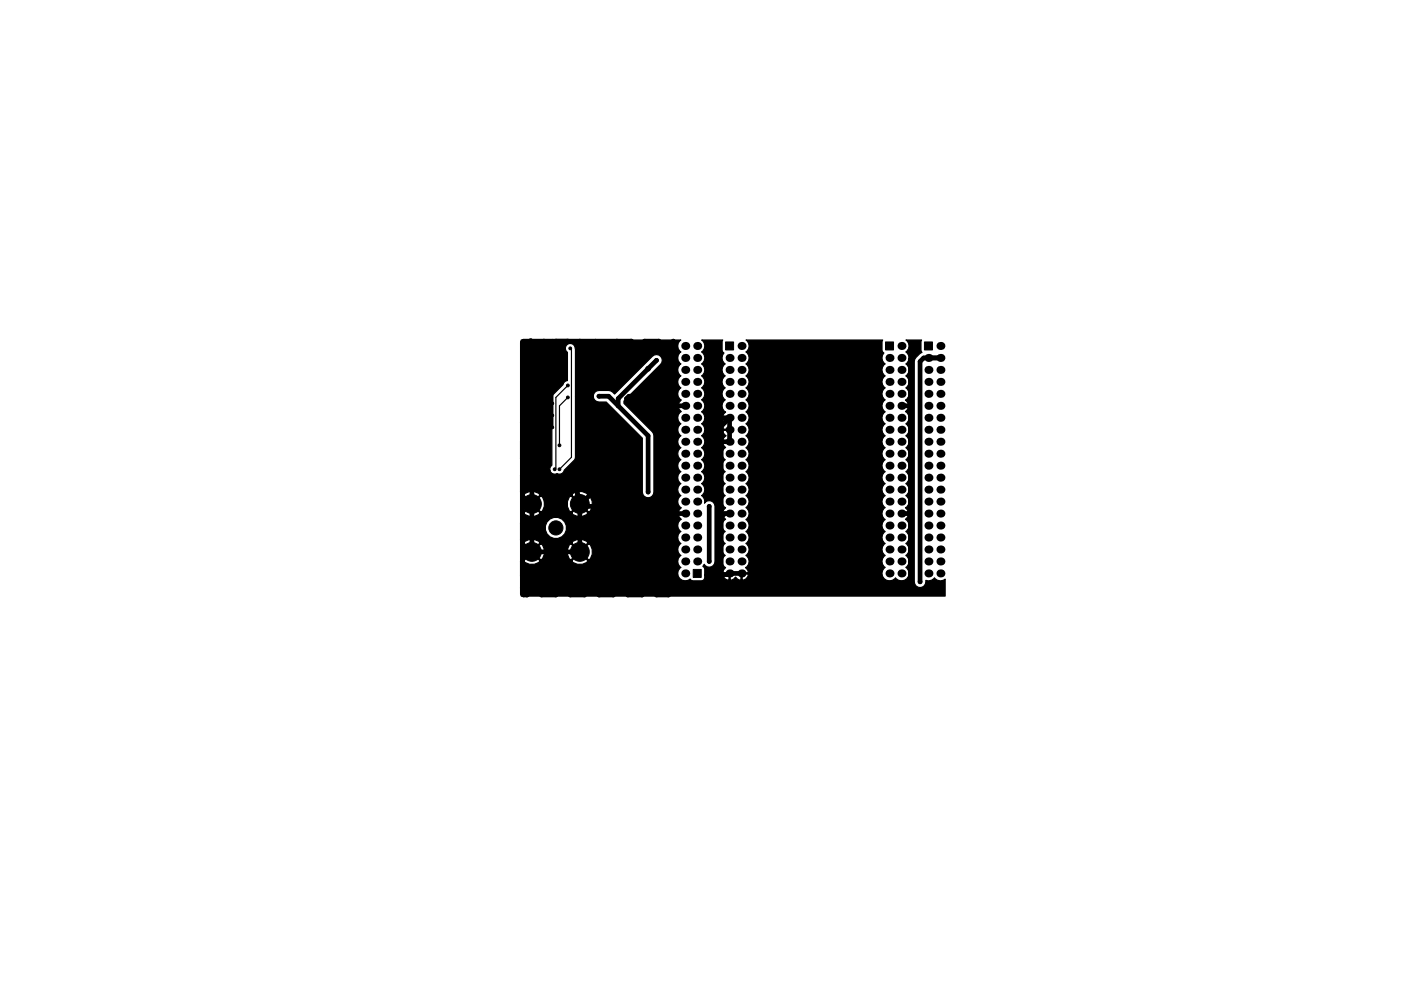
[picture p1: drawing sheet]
<svg xmlns="http://www.w3.org/2000/svg" width="297mm" height="210mm" viewBox="0 0 297 210" stroke-linecap="round" stroke-linejoin="round" font-family="sans-serif">
<g fill="#000" stroke="#000" stroke-width=".21">
<path d="M153.8 72.6h1.7v1.7h-1.7zM187.7 72.6h1.7v1.7h-1.7zM196 72.6h1.7v1.7h-1.7zM147 120.8h1.7v1.7h-1.7z"/>
<circle cx="112.5" cy="72.4" r=".5"/>
<circle cx="115.3" cy="72.4" r=".4"/>
<circle cx="117.1" cy="78" r=".3"/>
<circle cx="117.1" cy="75.4" r=".3"/>
<circle cx="117.9" cy="72.4" r=".4"/>
<circle cx="120.4" cy="72.4" r=".4"/>
<circle cx="120.9" cy="73.9" r=".3"/>
<circle cx="122.9" cy="72.4" r=".4"/>
<circle cx="126.2" cy="75.4" r=".3"/>
<circle cx="126.2" cy="77.5" r=".3"/>
<circle cx="130.8" cy="72.4" r=".4"/>
<circle cx="133.9" cy="74.9" r=".5"/>
<circle cx="133.9" cy="72.4" r=".4"/>
<circle cx="136.7" cy="72.4" r=".4"/>
<circle cx="137.4" cy="78.2" r=".5"/>
<circle cx="139.2" cy="76.4" r=".4"/>
<circle cx="139.7" cy="72.4" r=".4"/>
<circle cx="142.7" cy="72.4" r=".4"/>
<circle cx="193" cy="76.2" r=".4"/>
<circle cx="110.7" cy="93.7" r=".4"/>
<circle cx="110.7" cy="89.7" r=".4"/>
<circle cx="110.7" cy="97.3" r=".4"/>
<circle cx="117.1" cy="88.1" r=".3"/>
<circle cx="117.1" cy="85.6" r=".3"/>
<circle cx="117.1" cy="83.1" r=".3"/>
<circle cx="117.1" cy="90.7" r=".3"/>
<circle cx="117.1" cy="80.5" r=".3"/>
<circle cx="117.6" cy="99.6" r=".3"/>
<circle cx="118.6" cy="99.6" r=".3"/>
<circle cx="118.6" cy="94.5" r=".3"/>
<circle cx="120.4" cy="84.3" r=".3"/>
<circle cx="120.4" cy="81.8" r=".3"/>
<circle cx="122.4" cy="92.5" r=".4"/>
<circle cx="125.5" cy="91.9" r=".4"/>
<circle cx="126.2" cy="82" r=".3"/>
<circle cx="127" cy="84.1" r=".4"/>
<circle cx="127.3" cy="98.8" r=".5"/>
<circle cx="127.5" cy="91.9" r=".4"/>
<circle cx="131.6" cy="91.9" r=".4"/>
<circle cx="132.8" cy="84.6" r=".4"/>
<circle cx="135.4" cy="84.1" r=".5"/>
<circle cx="143.3" cy="93.2" r=".4"/>
<circle cx="143.3" cy="89.1" r=".4"/>
<circle cx="143.3" cy="86.1" r=".4"/>
<circle cx="143.3" cy="97.3" r=".4"/>
<circle cx="143.3" cy="83.6" r=".4"/>
<circle cx="143.3" cy="95.2" r=".4"/>
<circle cx="143.3" cy="91.2" r=".4"/>
<circle cx="143.3" cy="99.3" r=".4"/>
<circle cx="151.4" cy="82" r=".4"/>
<circle cx="110.7" cy="119.1" r=".4"/>
<circle cx="110.7" cy="114.5" r=".4"/>
<circle cx="110.7" cy="100.8" r=".4"/>
<circle cx="110.7" cy="111" r=".4"/>
<circle cx="110.7" cy="104.4" r=".4"/>
<circle cx="112.8" cy="106.9" r="2"/>
<circle cx="112.8" cy="117.1" r="2"/>
<circle cx="117.9" cy="112" r="1.5"/>
<circle cx="122.9" cy="117.1" r="2"/>
<circle cx="122.9" cy="106.9" r="2"/>
<circle cx="127.3" cy="102.9" r=".5"/>
<circle cx="134.9" cy="107.4" r=".4"/>
<circle cx="137.4" cy="104.4" r=".4"/>
<circle cx="143.3" cy="111.5" r=".4"/>
<circle cx="143.3" cy="101.3" r=".4"/>
<circle cx="143.3" cy="109.5" r=".4"/>
<circle cx="143.3" cy="105.4" r=".4"/>
<circle cx="143.3" cy="118.1" r=".4"/>
<circle cx="143.3" cy="103.4" r=".4"/>
<circle cx="143.3" cy="107.4" r=".4"/>
<circle cx="143.3" cy="116.1" r=".4"/>
<circle cx="143.3" cy="113.5" r=".4"/>
<circle cx="150.4" cy="107.4" r=".4"/>
<circle cx="150.4" cy="119.1" r=".4"/>
<circle cx="193" cy="119.4" r=".4"/>
<circle cx="193" cy="116.1" r=".4"/>
<circle cx="110.7" cy="122.2" r=".4"/>
<circle cx="110.7" cy="124.7" r=".4"/>
<circle cx="111.8" cy="126.2" r=".4"/>
<circle cx="114.8" cy="126.2" r=".4"/>
<circle cx="117.9" cy="126.2" r=".4"/>
<circle cx="120.9" cy="126.2" r=".4"/>
<circle cx="124" cy="126.2" r=".4"/>
<circle cx="127" cy="126.2" r=".4"/>
<circle cx="130" cy="126.2" r=".4"/>
<circle cx="133.1" cy="126.2" r=".4"/>
<circle cx="136.1" cy="126.2" r=".4"/>
<circle cx="139.2" cy="126.2" r=".4"/>
<circle cx="141.7" cy="126.2" r=".4"/>
<circle cx="143.3" cy="122.2" r=".4"/>
<circle cx="143.3" cy="125.2" r=".4"/>
<circle cx="143.3" cy="120.1" r=".4"/>
<circle cx="195.1" cy="123.4" r=".4"/>
</g>
<g fill="#000">
<circle cx="145.3" cy="78.5" r=".85"/>
<circle cx="145.3" cy="75.9" r=".85"/>
<circle cx="145.3" cy="73.4" r=".85"/>
<circle cx="147.8" cy="78.5" r=".85"/>
<circle cx="147.8" cy="73.4" r=".85"/>
<circle cx="147.8" cy="75.9" r=".85"/>
<circle cx="154.7" cy="78.5" r=".85"/>
<circle cx="154.7" cy="75.9" r=".85"/>
<circle cx="157.2" cy="78.5" r=".85"/>
<circle cx="157.2" cy="73.4" r=".85"/>
<circle cx="157.2" cy="75.9" r=".85"/>
<circle cx="188.6" cy="78.5" r=".85"/>
<circle cx="188.6" cy="75.9" r=".85"/>
<circle cx="191.1" cy="78.5" r=".85"/>
<circle cx="191.1" cy="73.4" r=".85"/>
<circle cx="191.1" cy="75.9" r=".85"/>
<circle cx="196.8" cy="78.5" r=".85"/>
<circle cx="196.8" cy="75.9" r=".85"/>
<circle cx="199.4" cy="73.4" r=".85"/>
<circle cx="199.4" cy="78.5" r=".85"/>
<circle cx="199.4" cy="75.9" r=".85"/>
<circle cx="145.3" cy="96.3" r=".85"/>
<circle cx="145.3" cy="88.6" r=".85"/>
<circle cx="145.3" cy="83.6" r=".85"/>
<circle cx="145.3" cy="81" r=".85"/>
<circle cx="145.3" cy="93.7" r=".85"/>
<circle cx="145.3" cy="86.1" r=".85"/>
<circle cx="145.3" cy="98.8" r=".85"/>
<circle cx="145.3" cy="91.2" r=".85"/>
<circle cx="147.8" cy="93.7" r=".85"/>
<circle cx="147.8" cy="88.6" r=".85"/>
<circle cx="147.8" cy="86.1" r=".85"/>
<circle cx="147.8" cy="96.3" r=".85"/>
<circle cx="147.8" cy="91.2" r=".85"/>
<circle cx="147.8" cy="81" r=".85"/>
<circle cx="147.8" cy="98.8" r=".85"/>
<circle cx="147.8" cy="83.6" r=".85"/>
<circle cx="154.7" cy="93.7" r=".85"/>
<circle cx="154.7" cy="96.3" r=".85"/>
<circle cx="154.7" cy="81" r=".85"/>
<circle cx="154.7" cy="86.1" r=".85"/>
<circle cx="154.7" cy="83.6" r=".85"/>
<circle cx="154.7" cy="91.2" r=".85"/>
<circle cx="154.7" cy="98.8" r=".85"/>
<circle cx="154.7" cy="88.6" r=".85"/>
<circle cx="157.2" cy="96.3" r=".85"/>
<circle cx="157.2" cy="93.7" r=".85"/>
<circle cx="157.2" cy="86.1" r=".85"/>
<circle cx="157.2" cy="81" r=".85"/>
<circle cx="157.2" cy="83.6" r=".85"/>
<circle cx="157.2" cy="88.6" r=".85"/>
<circle cx="157.2" cy="91.2" r=".85"/>
<circle cx="157.2" cy="98.8" r=".85"/>
<circle cx="188.6" cy="96.3" r=".85"/>
<circle cx="188.6" cy="88.6" r=".85"/>
<circle cx="188.6" cy="86.1" r=".85"/>
<circle cx="188.6" cy="93.7" r=".85"/>
<circle cx="188.6" cy="83.6" r=".85"/>
<circle cx="188.6" cy="91.2" r=".85"/>
<circle cx="188.6" cy="81" r=".85"/>
<circle cx="188.6" cy="98.8" r=".85"/>
<circle cx="191.1" cy="86.1" r=".85"/>
<circle cx="191.1" cy="83.6" r=".85"/>
<circle cx="191.1" cy="88.6" r=".85"/>
<circle cx="191.1" cy="91.2" r=".85"/>
<circle cx="191.1" cy="93.7" r=".85"/>
<circle cx="191.1" cy="96.3" r=".85"/>
<circle cx="191.1" cy="81" r=".85"/>
<circle cx="191.1" cy="98.8" r=".85"/>
<circle cx="196.8" cy="91.2" r=".85"/>
<circle cx="196.8" cy="86.1" r=".85"/>
<circle cx="196.8" cy="88.6" r=".85"/>
<circle cx="196.8" cy="93.7" r=".85"/>
<circle cx="196.8" cy="81" r=".85"/>
<circle cx="196.8" cy="83.6" r=".85"/>
<circle cx="196.8" cy="96.3" r=".85"/>
<circle cx="196.8" cy="98.8" r=".85"/>
<circle cx="199.4" cy="88.6" r=".85"/>
<circle cx="199.4" cy="83.6" r=".85"/>
<circle cx="199.4" cy="86.1" r=".85"/>
<circle cx="199.4" cy="91.2" r=".85"/>
<circle cx="199.4" cy="93.7" r=".85"/>
<circle cx="199.4" cy="96.3" r=".85"/>
<circle cx="199.4" cy="81" r=".85"/>
<circle cx="199.4" cy="98.8" r=".85"/>
<circle cx="145.3" cy="114" r=".85"/>
<circle cx="145.3" cy="119.1" r=".85"/>
<circle cx="145.3" cy="116.6" r=".85"/>
<circle cx="145.3" cy="109" r=".85"/>
<circle cx="145.3" cy="101.3" r=".85"/>
<circle cx="145.3" cy="111.5" r=".85"/>
<circle cx="145.3" cy="103.9" r=".85"/>
<circle cx="145.3" cy="106.4" r=".85"/>
<circle cx="147.8" cy="109" r=".85"/>
<circle cx="147.8" cy="116.6" r=".85"/>
<circle cx="147.8" cy="103.9" r=".85"/>
<circle cx="147.8" cy="119.1" r=".85"/>
<circle cx="147.8" cy="114" r=".85"/>
<circle cx="147.8" cy="111.5" r=".85"/>
<circle cx="147.8" cy="101.3" r=".85"/>
<circle cx="147.8" cy="106.4" r=".85"/>
<circle cx="154.7" cy="103.9" r=".85"/>
<circle cx="154.7" cy="109" r=".85"/>
<circle cx="154.7" cy="116.6" r=".85"/>
<circle cx="154.7" cy="119.1" r=".85"/>
<circle cx="154.7" cy="111.5" r=".85"/>
<circle cx="154.7" cy="114" r=".85"/>
<circle cx="154.7" cy="101.3" r=".85"/>
<circle cx="154.7" cy="106.4" r=".85"/>
<circle cx="157.2" cy="114" r=".85"/>
<circle cx="157.2" cy="119.1" r=".85"/>
<circle cx="157.2" cy="106.4" r=".85"/>
<circle cx="157.2" cy="111.5" r=".85"/>
<circle cx="157.2" cy="116.6" r=".85"/>
<circle cx="157.2" cy="101.3" r=".85"/>
<circle cx="157.2" cy="109" r=".85"/>
<circle cx="157.2" cy="103.9" r=".85"/>
<circle cx="188.6" cy="109" r=".85"/>
<circle cx="188.6" cy="116.6" r=".85"/>
<circle cx="188.6" cy="101.3" r=".85"/>
<circle cx="188.6" cy="103.9" r=".85"/>
<circle cx="188.6" cy="106.4" r=".85"/>
<circle cx="188.6" cy="111.5" r=".85"/>
<circle cx="188.6" cy="119.1" r=".85"/>
<circle cx="188.6" cy="114" r=".85"/>
<circle cx="191.1" cy="111.5" r=".85"/>
<circle cx="191.1" cy="109" r=".85"/>
<circle cx="191.1" cy="116.6" r=".85"/>
<circle cx="191.1" cy="101.3" r=".85"/>
<circle cx="191.1" cy="103.9" r=".85"/>
<circle cx="191.1" cy="106.4" r=".85"/>
<circle cx="191.1" cy="119.1" r=".85"/>
<circle cx="191.1" cy="114" r=".85"/>
<circle cx="196.8" cy="101.3" r=".85"/>
<circle cx="196.8" cy="109" r=".85"/>
<circle cx="196.8" cy="116.6" r=".85"/>
<circle cx="196.8" cy="103.9" r=".85"/>
<circle cx="196.8" cy="106.4" r=".85"/>
<circle cx="196.8" cy="111.5" r=".85"/>
<circle cx="196.8" cy="119.1" r=".85"/>
<circle cx="196.8" cy="114" r=".85"/>
<circle cx="199.4" cy="116.6" r=".85"/>
<circle cx="199.4" cy="101.3" r=".85"/>
<circle cx="199.4" cy="103.9" r=".85"/>
<circle cx="199.4" cy="106.4" r=".85"/>
<circle cx="199.4" cy="109" r=".85"/>
<circle cx="199.4" cy="114" r=".85"/>
<circle cx="199.4" cy="111.5" r=".85"/>
<circle cx="199.4" cy="119.1" r=".85"/>
<circle cx="145.3" cy="121.7" r=".85"/>
<circle cx="154.7" cy="121.7" r=".85"/>
<circle cx="157.2" cy="121.7" r=".85"/>
<circle cx="188.6" cy="121.7" r=".85"/>
<circle cx="191.1" cy="121.7" r=".85"/>
<circle cx="196.8" cy="121.7" r=".85"/>
<circle cx="199.4" cy="121.7" r=".85"/>
</g>
<g fill="none" stroke="#000" stroke-width="1">
<path d="M112.5 72.4l.3 .2v44.5M126.2 72.4v9.6h-3.3l-.5 .5v22.4l.5 .5v11.7h-12.2M133.9 74.9v-2.5h-22.9l-.3 .2v53.4l.3 .2h.8M136.7 72.4h3M139.2 76.4l-8.1 8.2v1.5M142.7 72.4l.6 .5M143.3 72.6v22.6M193 76.3v46.6l-.7 .8h-48.8l-.2-.3M199.4 75.9h-3.6l-.7 .8v46.7M127 84.1h2l8.4 8.4v11.9M127.3 98.8v4.1l-4.1 4h-.3l.5 .5h19.9M131.6 91.9h-8.7l-.5 .6"/>
<path d="M143.3 97.3v2M143.3 84.1h-10l-.5 .5M145.3 86.1h-1.8l-.2 .3M151.4 82v5.6l1 1h2.3M154.7 88.6v5.1h-1.8M154.7 88.6l-1.8 1.8v32.8l-.5 .5M191.1 86.1h1.9M110.7 106.9h2.1M143.3 101.3v2.1M143.3 105.4v19.8M143.3 109h2M150.4 107.4v11.7"/>
<path d="M154.7 109h-1l-.8 .7M193 108.5l-.5 .5h-1.4M114.8 126.2h3.1M120.9 126.2h3.1M127 126.2h3M133.1 126.2h3M139.2 126.2h2.5M157.2 121.7h-2.5l-.3 .2h-1.5"/>
</g>
<path d="M117.1 72.4v18.3h-4.3" fill="none" stroke="#000" stroke-width=".5"/>
<path d="M193.3 76.2l-.3 .1" fill="none" stroke="#000" stroke-width=".4"/>
<path d="M120.9 73.9l.3 .3v22.8l-2.6 2.6M120.4 81.8l-2.5 2.5v15l-.3 .3M120.4 84.3l-1.8 1.8v8.4" fill="none" stroke="#000" stroke-width=".25"/>
<path d="M110.5 72.1h33.9l-.3 .2a1.54 1.54 0 0 0 .3 2.4 1.51 1.51 0 0 0 0 2.5 1.51 1.51 0 0 0 0 2.6 1.51 1.51 0 0 0 0 2.5 1.51 1.51 0 0 0 .1 2.6l-.5 .4-.2 .4 .2 .3h1.4v.2h-1.4l-.2 .3 .2 .4 .5 .4-.4 .2a1.54 1.54 0 0 0 .3 2.4 1.51 1.51 0 0 0 0 2.6 1.51 1.51 0 0 0 0 2.5 1.51 1.51 0 0 0 0 2.5 1.51 1.51 0 0 0 0 2.6 1.51 1.51 0 0 0 0 2.5 1.51 1.51 0 0 0 0 2.6 1.51 1.51 0 0 0 .1 2.5l-.5 .5-.2 .4 .2 .2h1.4v.3h-1.4l-.2 .2 .2 .4 .5 .5-.4 .2a1.54 1.54 0 0 0 .3 2.4 1.51 1.51 0 0 0 0 2.5 1.51 1.51 0 0 0 0 2.6 1.51 1.51 0 0 0 0 2.5 1.57 1.57 0 0 0-.4 2.3 1.57 1.57 0 0 0 2.3 .1l.7 .5h1.7a.87 .87 0 0 0 .7-1.3h3.8l.6 .9 .5 .2 .3-.1v-1.2h.2v1.2l.2 .1 .6-.2 .4-.5 .3 .5 .6 .2 .2-.1v-1.2h.3v1.2l.2 .1a1.08 1.08 0 0 0 .9-1.3h-5.1l-.2 .2h-3.8v-1.5l-.4-.3 .3-.5 .2 .3a1.23 1.23 0 0 0 1.3 .3 1.23 1.23 0 0 0 .8-1.2l-.1-12.1a1.2 1.2 0 0 0-2.1-.2 1.42 1.42 0 0 0-.7-1.6 1.51 1.51 0 0 0 0-2.6 1.51 1.51 0 0 0 0-2.5 1.51 1.51 0 0 0 0-2.6 1.51 1.51 0 0 0 0-2.5 1.51 1.51 0 0 0 0-2.5l.7-1h3.8l.2 .4 .6 .6-.6 .5-.2 .4 .2 .2h1.2v-2.3h-1.2l-.2 .2h-3.8a1.42 1.42 0 0 0-.7-1.6l.7-.9h3.8l.2 .4 .6 .5-.6 .5-.2 .4 .2 .3h1.2v-2.3h-1.2l-.2 .2h-3.8a1.42 1.42 0 0 0-.7-1.6 1.51 1.51 0 0 0 0-2.6 1.51 1.51 0 0 0 0-2.5 1.51 1.51 0 0 0 0-2.5 1.51 1.51 0 0 0 0-2.6 1.51 1.51 0 0 0 0-2.5 1.51 1.51 0 0 0 .1-2.6h4.4l-.1 .5v1.7l.4 .6-.3 .4a1.5 1.5 0 0 0 .6 1.9 1.51 1.51 0 0 0 0 2.6 1.51 1.51 0 0 0 0 2.5 1.51 1.51 0 0 0 0 2.5 1.51 1.51 0 0 0 .1 2.6l-.5 .5-.2 .4 .2 .2h1.4v5.3h-1.4l-.2 .3 .2 .4 .5 .4-.4 .2a1.54 1.54 0 0 0 .3 2.4 1.51 1.51 0 0 0 0 2.6 1.51 1.51 0 0 0 0 2.5 1.51 1.51 0 0 0 0 2.6 1.51 1.51 0 0 0 .1 2.5l-.5 .5-.2 .4 .2 .2h1.4v.3h-1.4l-.2 .2 .2 .4 .5 .5-.4 .2a1.54 1.54 0 0 0 .3 2.4 1.51 1.51 0 0 0 0 2.5 1.51 1.51 0 0 0 0 2.6 1.51 1.51 0 0 0 .1 2.5l-.5 .5-.2 .4 .2 .2h5.1l.2-.2-.2-.4-.4-.5 .3-.2a1.54 1.54 0 0 0-.3-2.3 1.51 1.51 0 0 0 0-2.6 1.51 1.51 0 0 0 0-2.5 1.51 1.51 0 0 0 0-2.6 1.51 1.51 0 0 0 0-2.5 1.51 1.51 0 0 0 0-2.5 1.51 1.51 0 0 0 0-2.6 1.51 1.51 0 0 0 0-2.5 1.51 1.51 0 0 0 0-2.6 1.51 1.51 0 0 0 0-2.5 1.51 1.51 0 0 0 0-2.5 1.51 1.51 0 0 0 0-2.6 1.51 1.51 0 0 0 0-2.5 1.51 1.51 0 0 0 0-2.6 1.51 1.51 0 0 0 0-2.5 1.51 1.51 0 0 0 0-2.5 1.51 1.51 0 0 0 0-2.6 1.51 1.51 0 0 0 0-2.5 1.51 1.51 0 0 0 .1-2.6h28.9l-.1 .5v1.7l.4 .6-.3 .4a1.5 1.5 0 0 0 .6 1.9 1.51 1.51 0 0 0 0 2.6 1.51 1.51 0 0 0 0 2.5 1.51 1.51 0 0 0 0 2.5 1.51 1.51 0 0 0 0 2.6 1.51 1.51 0 0 0 0 2.5 1.51 1.51 0 0 0 0 2.6 1.51 1.51 0 0 0 0 2.5 1.51 1.51 0 0 0 0 2.5 1.51 1.51 0 0 0 0 2.6 1.51 1.51 0 0 0 0 2.5 1.51 1.51 0 0 0 0 2.6 1.51 1.51 0 0 0 0 2.5 1.51 1.51 0 0 0 0 2.5 1.51 1.51 0 0 0 0 2.6 1.51 1.51 0 0 0 0 2.5 1.51 1.51 0 0 0 0 2.6 1.51 1.51 0 0 0 0 2.5 1.57 1.57 0 0 0-.2 2.4 1.57 1.57 0 0 0 2.4-.2 1.57 1.57 0 0 0 2.4 .2 1.57 1.57 0 0 0-.3-2.4 1.51 1.51 0 0 0 0-2.5 1.51 1.51 0 0 0 0-2.6 1.51 1.51 0 0 0 0-2.5 1.51 1.51 0 0 0 0-2.6l.4-.5 .2-.4-.1-.2h-1.5v-.3h1.5l.1-.2-.2-.4-.4-.5 .3-.2a1.54 1.54 0 0 0-.3-2.3 1.51 1.51 0 0 0 0-2.6 1.51 1.51 0 0 0 0-2.5 1.51 1.51 0 0 0 0-2.6 1.51 1.51 0 0 0 0-2.5 1.51 1.51 0 0 0 0-2.5 1.51 1.51 0 0 0 0-2.6 1.51 1.51 0 0 0 0-2.6l.4-.4 .2-.4-.1-.3h-1.5v-.2h1.5l.1-.3-.2-.4-.4-.4 .3-.2a1.54 1.54 0 0 0-.3-2.4 1.51 1.51 0 0 0 0-2.5 1.51 1.51 0 0 0 0-2.6 1.51 1.51 0 0 0 0-2.5 1.51 1.51 0 0 0 .1-2.6h3.3l-.1 .5v1.7l.2 .5h-.1a2.78 2.78 0 0 0-1.6 1.9l.1 47.2a1.25 1.25 0 0 0 1.6 .7 1.25 1.25 0 0 0 .8-1.5 1.55 1.55 0 0 0 1.8-.5 1.56 1.56 0 0 0 2.3 .3v3.6h-89.9v-7.5h.6a2.16 2.16 0 0 0 3.4 0h6.7l.3 .3a2.29 2.29 0 0 0 3.1-.3l-1.7-1.7-1.7 1.7h-6.7l-1.7-1.7-1.7 1.7h-.6v-.5l.4 .3 1.7-1.7h.4l1.7 1.7 .3-.2 .4-1v-1h4.9v1l.4 1 .4 .2 1.7-1.7h.3l1.7 1.7a2.16 2.16 0 0 0 0-3.4l-1.7 1.7h-.3l-1.7-1.7-.4 .2-.4 1h-4.9l-.4-1-.3-.2-1.7 1.7h-.4l-1.7-1.7-.4 .3v-.5h.6l1.7 1.7 1.7-1.7h6.7l1.7 1.7 1.7-1.7-.2-.4a2.29 2.29 0 0 0-3.2 .4h-6.7l-.2-.4a2.29 2.29 0 0 0-3.2 .4h-.6v-2.8h5.1l.4 .9a2.27 2.27 0 0 0 3.7 0 2.27 2.27 0 0 0-1.4-3.5 2.27 2.27 0 0 0-2.7 2.6h-5.1v-3.6h.6l.2 .4a2.29 2.29 0 0 0 3.2-.4h6.7l.3 .4a2.29 2.29 0 0 0 3.1-.4l-1.7-1.7-1.7 1.7h-6.7l-1.7-1.7-1.7 1.7h-.6v-.5l.4 .3 1.7-1.7h.4l1.7 1.7 .3-.2 .4-1v-1h4.9v1.1l.4 .9 .4 .2 1.7-1.7h.3l1.7 1.7a2.16 2.16 0 0 0 0-3.4l-1.7 1.7h-.3l-1.7-1.7-.4 .3-.4 .9h-4.9l-.4-.9-.3-.3-1.7 1.7h-.4l-1.7-1.7-.4 .3v-.4h.6l1.7 1.6 1.7-1.6h6.7l1.7 1.6 1.7-1.6-.2-.4a2.29 2.29 0 0 0-3.2 .4h-6.7l-.2-.4a2.29 2.29 0 0 0-3.2 .4h-.6v-5.3h6.1l.1 .3a1.02 1.02 0 0 0 1.4 .4 1.03 1.03 0 0 0 1.5-.8l2.2-2.1 .2-.6v-12.9h3.8l.3 .8 .4 .3 2 .1 7.7 7.7v11.4a1.23 1.23 0 0 0 1.2 1.2 1.23 1.23 0 0 0 1.2-1.2l-.1-12.4-6.2-6.4v-.5l8-8.2a1.23 1.23 0 0 0-.4-1.5 1.23 1.23 0 0 0-1.6 .2l-8 8-.8-.7a4.1 4.1 0 0 0-3.4 .3l-.3 .9h-3.8v-9.9a1.06 1.06 0 0 0-1.4-1.3 1.06 1.06 0 0 0-.3 1.9v6h-.1a1.03 1.03 0 0 0-.8 .8l-2.1 2.1-.3 .6v14.4l-.4 .7v.4h-6.1zM199.3 78.3l.2 .1v.2h-.3zM196.7 119h.3v.2l-.3 .1zM196.7 113.9h.3v.3h-.3z" fill="#000" stroke="#000" stroke-width=".25"/>
</svg>
